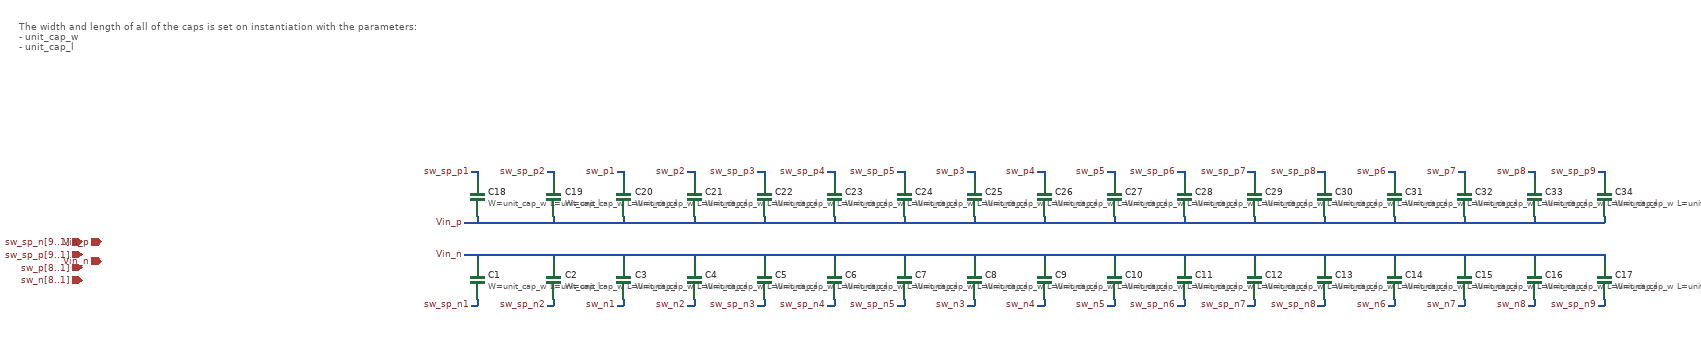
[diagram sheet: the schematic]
v {xschem version=3.0.0 file_version=1.2 }
G {}
K {}
V {}
S {}
E {}
T {The width and length of all of the caps is set on instantiation with the parameters:
- unit_cap_w
- unit_cap_l

} 40 -630 0 0 0.4 0.4 {}
N 750 -180 760 -180 {
lab=sw_sp_n1}
N 760 -190 760 -180 {
lab=sw_sp_n1}
N 870 -180 880 -180 {
lab=sw_sp_n2}
N 880 -190 880 -180 {
lab=sw_sp_n2}
N 1200 -180 1210 -180 {
lab=sw_sp_n3}
N 1210 -190 1210 -180 {
lab=sw_sp_n3}
N 1310 -180 1320 -180 {
lab=sw_sp_n4}
N 1320 -190 1320 -180 {
lab=sw_sp_n4}
N 1420 -180 1430 -180 {
lab=sw_sp_n5}
N 1430 -190 1430 -180 {
lab=sw_sp_n5}
N 1860 -180 1870 -180 {
lab=sw_sp_n6}
N 1870 -190 1870 -180 {
lab=sw_sp_n6}
N 1970 -180 1980 -180 {
lab=sw_sp_n7}
N 1980 -190 1980 -180 {
lab=sw_sp_n7}
N 2080 -180 2090 -180 {
lab=sw_sp_n8}
N 2090 -190 2090 -180 {
lab=sw_sp_n8}
N 2520 -180 2530 -180 {
lab=sw_sp_n9}
N 2530 -190 2530 -180 {
lab=sw_sp_n9}
N 980 -180 990 -180 {
lab=sw_n1}
N 990 -190 990 -180 {
lab=sw_n1}
N 1090 -180 1100 -180 {
lab=sw_n2}
N 1100 -190 1100 -180 {
lab=sw_n2}
N 1530 -180 1540 -180 {
lab=sw_n3}
N 1540 -190 1540 -180 {
lab=sw_n3}
N 1640 -180 1650 -180 {
lab=sw_n4}
N 1650 -190 1650 -180 {
lab=sw_n4}
N 1750 -180 1760 -180 {
lab=sw_n5}
N 1760 -190 1760 -180 {
lab=sw_n5}
N 2190 -180 2200 -180 {
lab=sw_n6}
N 2200 -190 2200 -180 {
lab=sw_n6}
N 2300 -180 2310 -180 {
lab=sw_n7}
N 2310 -190 2310 -180 {
lab=sw_n7}
N 2410 -180 2420 -180 {
lab=sw_n8}
N 2420 -190 2420 -180 {
lab=sw_n8}
N 740 -260 2530 -260 {
lab=Vin_n}
N 2530 -260 2530 -250 {
lab=Vin_n}
N 2420 -260 2420 -250 {
lab=Vin_n}
N 2310 -260 2310 -250 {
lab=Vin_n}
N 2200 -260 2200 -250 {
lab=Vin_n}
N 2090 -260 2090 -250 {
lab=Vin_n}
N 1980 -260 1980 -250 {
lab=Vin_n}
N 1870 -260 1870 -250 {
lab=Vin_n}
N 1760 -260 1760 -250 {
lab=Vin_n}
N 1650 -260 1650 -250 {
lab=Vin_n}
N 1540 -260 1540 -250 {
lab=Vin_n}
N 1430 -260 1430 -250 {
lab=Vin_n}
N 1320 -260 1320 -250 {
lab=Vin_n}
N 1210 -260 1210 -250 {
lab=Vin_n}
N 1100 -260 1100 -250 {
lab=Vin_n}
N 990 -260 990 -250 {
lab=Vin_n}
N 880 -260 880 -250 {
lab=Vin_n}
N 760 -260 760 -250 {
lab=Vin_n}
N 750 -390 760 -390 {
lab=sw_sp_p1}
N 760 -390 760 -380 {
lab=sw_sp_p1}
N 870 -390 880 -390 {
lab=sw_sp_p2}
N 880 -390 880 -380 {
lab=sw_sp_p2}
N 1200 -390 1210 -390 {
lab=sw_sp_p3}
N 1210 -390 1210 -380 {
lab=sw_sp_p3}
N 1310 -390 1320 -390 {
lab=sw_sp_p4}
N 1320 -390 1320 -380 {
lab=sw_sp_p4}
N 1420 -390 1430 -390 {
lab=sw_sp_p5}
N 1430 -390 1430 -380 {
lab=sw_sp_p5}
N 1860 -390 1870 -390 {
lab=sw_sp_p6}
N 1870 -390 1870 -380 {
lab=sw_sp_p6}
N 1970 -390 1980 -390 {
lab=sw_sp_p7}
N 1980 -390 1980 -380 {
lab=sw_sp_p7}
N 2080 -390 2090 -390 {
lab=sw_sp_p8}
N 2090 -390 2090 -380 {
lab=sw_sp_p8}
N 2520 -390 2530 -390 {
lab=sw_sp_p9}
N 2530 -390 2530 -380 {
lab=sw_sp_p9}
N 980 -390 990 -390 {
lab=sw_p1}
N 990 -390 990 -380 {
lab=sw_p1}
N 1090 -390 1100 -390 {
lab=sw_p2}
N 1100 -390 1100 -380 {
lab=sw_p2}
N 1530 -390 1540 -390 {
lab=sw_p3}
N 1540 -390 1540 -380 {
lab=sw_p3}
N 1640 -390 1650 -390 {
lab=sw_p4}
N 1650 -390 1650 -380 {
lab=sw_p4}
N 1750 -390 1760 -390 {
lab=sw_p5}
N 1760 -390 1760 -380 {
lab=sw_p5}
N 2190 -390 2200 -390 {
lab=sw_p6}
N 2200 -390 2200 -380 {
lab=sw_p6}
N 2300 -390 2310 -390 {
lab=sw_p7}
N 2310 -390 2310 -380 {
lab=sw_p7}
N 2410 -390 2420 -390 {
lab=sw_n8}
N 2420 -390 2420 -380 {
lab=sw_n8}
N 740 -310 2530 -310 {
lab=Vin_p}
N 2530 -320 2530 -310 {
lab=Vin_p}
N 2420 -320 2420 -310 {
lab=Vin_p}
N 2310 -320 2310 -310 {
lab=Vin_p}
N 2200 -320 2200 -310 {
lab=Vin_p}
N 2090 -320 2090 -310 {
lab=Vin_p}
N 1980 -320 1980 -310 {
lab=Vin_p}
N 1870 -320 1870 -310 {
lab=Vin_p}
N 1760 -320 1760 -310 {
lab=Vin_p}
N 1650 -320 1650 -310 {
lab=Vin_p}
N 1540 -320 1540 -310 {
lab=Vin_p}
N 1430 -320 1430 -310 {
lab=Vin_p}
N 1320 -320 1320 -310 {
lab=Vin_p}
N 1210 -320 1210 -310 {
lab=Vin_p}
N 1100 -320 1100 -310 {
lab=Vin_p}
N 990 -320 990 -310 {
lab=Vin_p}
N 880 -320 880 -310 {
lab=Vin_p}
N 760 -320 760 -310 {
lab=Vin_p}
C {devices/title.sym} 160 30 0 0 {name=l1 author="Dr. Aubrey Beal, Dr. Phillip Bailey, Micah Tseng"
}
C {sky130_fd_pr/cap_mim_m3_1.sym} 760 -220 0 0 {name=C1 model=cap_mim_m3_1 W=unit_cap_w L=unit_cap_l MF=128 spiceprefix=X
}
C {devices/ipin.sym} 140 -280 0 0 {name=p1 lab=sw_sp_n[9..1]
}
C {devices/iopin.sym} 170 -280 0 0 {name=p2 lab=Vin_p
}
C {devices/iopin.sym} 170 -250 0 0 {name=p3 lab=Vin_n
}
C {devices/ipin.sym} 140 -260 0 0 {name=p4 lab=sw_sp_p[9..1]
}
C {devices/ipin.sym} 140 -240 0 0 {name=p5 lab=sw_p[8..1]
}
C {devices/ipin.sym} 140 -220 0 0 {name=p6 lab=sw_n[8..1]
}
C {sky130_fd_pr/cap_mim_m3_1.sym} 880 -220 0 0 {name=C2 model=cap_mim_m3_1 W=unit_cap_w L=unit_cap_l MF=64 spiceprefix=X
}
C {sky130_fd_pr/cap_mim_m3_1.sym} 990 -220 0 0 {name=C3 model=cap_mim_m3_1 W=unit_cap_w L=unit_cap_l MF=128 spiceprefix=X
}
C {sky130_fd_pr/cap_mim_m3_1.sym} 1100 -220 0 0 {name=C4 model=cap_mim_m3_1 W=unit_cap_w L=unit_cap_l MF=64 spiceprefix=X
}
C {sky130_fd_pr/cap_mim_m3_1.sym} 1210 -220 0 0 {name=C5 model=cap_mim_m3_1 W=unit_cap_w L=unit_cap_l MF=32 spiceprefix=X
}
C {sky130_fd_pr/cap_mim_m3_1.sym} 1320 -220 0 0 {name=C6 model=cap_mim_m3_1 W=unit_cap_w L=unit_cap_l MF=16 spiceprefix=X
}
C {sky130_fd_pr/cap_mim_m3_1.sym} 1430 -220 0 0 {name=C7 model=cap_mim_m3_1 W=unit_cap_w L=unit_cap_l MF=8 spiceprefix=X
}
C {sky130_fd_pr/cap_mim_m3_1.sym} 1540 -220 0 0 {name=C8 model=cap_mim_m3_1 W=unit_cap_w L=unit_cap_l MF=32 spiceprefix=X
}
C {sky130_fd_pr/cap_mim_m3_1.sym} 1650 -220 0 0 {name=C9 model=cap_mim_m3_1 W=unit_cap_w L=unit_cap_l MF=16 spiceprefix=X
}
C {sky130_fd_pr/cap_mim_m3_1.sym} 1760 -220 0 0 {name=C10 model=cap_mim_m3_1 W=unit_cap_w L=unit_cap_l MF=8 spiceprefix=X
}
C {sky130_fd_pr/cap_mim_m3_1.sym} 1870 -220 0 0 {name=C11 model=cap_mim_m3_1 W=unit_cap_w L=unit_cap_l MF=4 spiceprefix=X
}
C {sky130_fd_pr/cap_mim_m3_1.sym} 1980 -220 0 0 {name=C12 model=cap_mim_m3_1 W=unit_cap_w L=unit_cap_l MF=2 spiceprefix=X
}
C {sky130_fd_pr/cap_mim_m3_1.sym} 2090 -220 0 0 {name=C13 model=cap_mim_m3_1 W=unit_cap_w L=unit_cap_l MF=1 spiceprefix=X
}
C {sky130_fd_pr/cap_mim_m3_1.sym} 2200 -220 0 0 {name=C14 model=cap_mim_m3_1 W=unit_cap_w L=unit_cap_l MF=4 spiceprefix=X
}
C {sky130_fd_pr/cap_mim_m3_1.sym} 2310 -220 0 0 {name=C15 model=cap_mim_m3_1 W=unit_cap_w L=unit_cap_l MF=2 spiceprefix=X
}
C {sky130_fd_pr/cap_mim_m3_1.sym} 2420 -220 0 0 {name=C16 model=cap_mim_m3_1 W=unit_cap_w L=unit_cap_l MF=1 spiceprefix=X
}
C {sky130_fd_pr/cap_mim_m3_1.sym} 2530 -220 0 0 {name=C17 model=cap_mim_m3_1 W=unit_cap_w L=unit_cap_l MF=1 spiceprefix=X
}
C {devices/lab_pin.sym} 750 -180 0 0 {name=l2 sig_type=std_logic lab=sw_sp_n1
}
C {devices/lab_pin.sym} 870 -180 0 0 {name=l3 sig_type=std_logic lab=sw_sp_n2
}
C {devices/lab_pin.sym} 1200 -180 0 0 {name=l4 sig_type=std_logic lab=sw_sp_n3
}
C {devices/lab_pin.sym} 1310 -180 0 0 {name=l5 sig_type=std_logic lab=sw_sp_n4
}
C {devices/lab_pin.sym} 1420 -180 0 0 {name=l6 sig_type=std_logic lab=sw_sp_n5
}
C {devices/lab_pin.sym} 1860 -180 0 0 {name=l7 sig_type=std_logic lab=sw_sp_n6
}
C {devices/lab_pin.sym} 1970 -180 0 0 {name=l8 sig_type=std_logic lab=sw_sp_n7
}
C {devices/lab_pin.sym} 2080 -180 0 0 {name=l9 sig_type=std_logic lab=sw_sp_n8
}
C {devices/lab_pin.sym} 2520 -180 0 0 {name=l10 sig_type=std_logic lab=sw_sp_n9
}
C {devices/lab_pin.sym} 980 -180 0 0 {name=l11 sig_type=std_logic lab=sw_n1
}
C {devices/lab_pin.sym} 1090 -180 0 0 {name=l12 sig_type=std_logic lab=sw_n2
}
C {devices/lab_pin.sym} 1530 -180 0 0 {name=l13 sig_type=std_logic lab=sw_n3
}
C {devices/lab_pin.sym} 1640 -180 0 0 {name=l14 sig_type=std_logic lab=sw_n4
}
C {devices/lab_pin.sym} 1750 -180 0 0 {name=l15 sig_type=std_logic lab=sw_n5
}
C {devices/lab_pin.sym} 2190 -180 0 0 {name=l16 sig_type=std_logic lab=sw_n6
}
C {devices/lab_pin.sym} 2300 -180 0 0 {name=l17 sig_type=std_logic lab=sw_n7
}
C {devices/lab_pin.sym} 2410 -180 0 0 {name=l19 sig_type=std_logic lab=sw_n8
}
C {devices/lab_pin.sym} 740 -260 0 0 {name=l18 sig_type=std_logic lab=Vin_n
}
C {sky130_fd_pr/cap_mim_m3_1.sym} 760 -350 2 1 {name=C18 model=cap_mim_m3_1 W=unit_cap_w L=unit_cap_l MF=128 spiceprefix=X
}
C {sky130_fd_pr/cap_mim_m3_1.sym} 880 -350 2 1 {name=C19 model=cap_mim_m3_1 W=unit_cap_w L=unit_cap_l MF=64 spiceprefix=X
}
C {sky130_fd_pr/cap_mim_m3_1.sym} 990 -350 2 1 {name=C20 model=cap_mim_m3_1 W=unit_cap_w L=unit_cap_l MF=128 spiceprefix=X
}
C {sky130_fd_pr/cap_mim_m3_1.sym} 1100 -350 2 1 {name=C21 model=cap_mim_m3_1 W=unit_cap_w L=unit_cap_l MF=64 spiceprefix=X
}
C {sky130_fd_pr/cap_mim_m3_1.sym} 1210 -350 2 1 {name=C22 model=cap_mim_m3_1 W=unit_cap_w L=unit_cap_l MF=32 spiceprefix=X
}
C {sky130_fd_pr/cap_mim_m3_1.sym} 1320 -350 2 1 {name=C23 model=cap_mim_m3_1 W=unit_cap_w L=unit_cap_l MF=16 spiceprefix=X
}
C {sky130_fd_pr/cap_mim_m3_1.sym} 1430 -350 2 1 {name=C24 model=cap_mim_m3_1 W=unit_cap_w L=unit_cap_l MF=8 spiceprefix=X
}
C {sky130_fd_pr/cap_mim_m3_1.sym} 1540 -350 2 1 {name=C25 model=cap_mim_m3_1 W=unit_cap_w L=unit_cap_l MF=32 spiceprefix=X
}
C {sky130_fd_pr/cap_mim_m3_1.sym} 1650 -350 2 1 {name=C26 model=cap_mim_m3_1 W=unit_cap_w L=unit_cap_l MF=16 spiceprefix=X
}
C {sky130_fd_pr/cap_mim_m3_1.sym} 1760 -350 2 1 {name=C27 model=cap_mim_m3_1 W=unit_cap_w L=unit_cap_l MF=8 spiceprefix=X
}
C {sky130_fd_pr/cap_mim_m3_1.sym} 1870 -350 2 1 {name=C28 model=cap_mim_m3_1 W=unit_cap_w L=unit_cap_l MF=4 spiceprefix=X
}
C {sky130_fd_pr/cap_mim_m3_1.sym} 1980 -350 2 1 {name=C29 model=cap_mim_m3_1 W=unit_cap_w L=unit_cap_l MF=2 spiceprefix=X
}
C {sky130_fd_pr/cap_mim_m3_1.sym} 2090 -350 2 1 {name=C30 model=cap_mim_m3_1 W=unit_cap_w L=unit_cap_l MF=1 spiceprefix=X
}
C {sky130_fd_pr/cap_mim_m3_1.sym} 2200 -350 2 1 {name=C31 model=cap_mim_m3_1 W=unit_cap_w L=unit_cap_l MF=4 spiceprefix=X
}
C {sky130_fd_pr/cap_mim_m3_1.sym} 2310 -350 2 1 {name=C32 model=cap_mim_m3_1 W=unit_cap_w L=unit_cap_l MF=2 spiceprefix=X
}
C {sky130_fd_pr/cap_mim_m3_1.sym} 2420 -350 2 1 {name=C33 model=cap_mim_m3_1 W=unit_cap_w L=unit_cap_l MF=1 spiceprefix=X
}
C {sky130_fd_pr/cap_mim_m3_1.sym} 2530 -350 2 1 {name=C34 model=cap_mim_m3_1 W=unit_cap_w L=unit_cap_l MF=1 spiceprefix=X
}
C {devices/lab_pin.sym} 750 -390 2 1 {name=l20 sig_type=std_logic lab=sw_sp_p1
}
C {devices/lab_pin.sym} 870 -390 2 1 {name=l21 sig_type=std_logic lab=sw_sp_p2
}
C {devices/lab_pin.sym} 1200 -390 2 1 {name=l22 sig_type=std_logic lab=sw_sp_p3
}
C {devices/lab_pin.sym} 1310 -390 2 1 {name=l23 sig_type=std_logic lab=sw_sp_p4
}
C {devices/lab_pin.sym} 1420 -390 2 1 {name=l24 sig_type=std_logic lab=sw_sp_p5
}
C {devices/lab_pin.sym} 1860 -390 2 1 {name=l25 sig_type=std_logic lab=sw_sp_p6
}
C {devices/lab_pin.sym} 1970 -390 2 1 {name=l26 sig_type=std_logic lab=sw_sp_p7
}
C {devices/lab_pin.sym} 2080 -390 2 1 {name=l27 sig_type=std_logic lab=sw_sp_p8
}
C {devices/lab_pin.sym} 2520 -390 2 1 {name=l28 sig_type=std_logic lab=sw_sp_p9
}
C {devices/lab_pin.sym} 980 -390 2 1 {name=l29 sig_type=std_logic lab=sw_p1
}
C {devices/lab_pin.sym} 1090 -390 2 1 {name=l30 sig_type=std_logic lab=sw_p2
}
C {devices/lab_pin.sym} 1530 -390 2 1 {name=l31 sig_type=std_logic lab=sw_p3
}
C {devices/lab_pin.sym} 1640 -390 2 1 {name=l32 sig_type=std_logic lab=sw_p4
}
C {devices/lab_pin.sym} 1750 -390 2 1 {name=l33 sig_type=std_logic lab=sw_p5
}
C {devices/lab_pin.sym} 2190 -390 2 1 {name=l34 sig_type=std_logic lab=sw_p6
}
C {devices/lab_pin.sym} 2300 -390 2 1 {name=l35 sig_type=std_logic lab=sw_p7
}
C {devices/lab_pin.sym} 2410 -390 2 1 {name=l36 sig_type=std_logic lab=sw_p8
}
C {devices/lab_pin.sym} 740 -310 2 1 {name=l37 sig_type=std_logic lab=Vin_p
}
